VERSION 5.7 ;
  NOWIREEXTENSIONATPIN ON ;
  DIVIDERCHAR "/" ;
  BUSBITCHARS "[]" ;
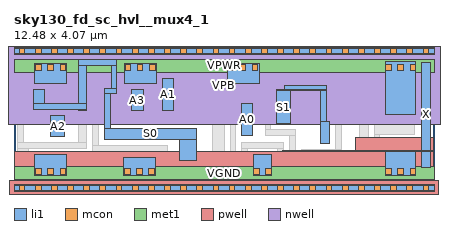
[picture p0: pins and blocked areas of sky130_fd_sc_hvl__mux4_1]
MACRO sky130_fd_sc_hvl__mux4_1
  CLASS BLOCK ;
  FOREIGN sky130_fd_sc_hvl__mux4_1 ;
  ORIGIN 0.000 0.000 ;
  SIZE 12.480 BY 4.070 ;
  PIN A0
    ANTENNAGATEAREA 0.420000 ;
    PORT
      LAYER li1 ;
        RECT 6.770 1.550 7.100 2.520 ;
    END
  END A0
  PIN A1
    ANTENNAGATEAREA 0.420000 ;
    PORT
      LAYER li1 ;
        RECT 4.400 2.300 4.730 3.260 ;
    END
  END A1
  PIN A2
    ANTENNAGATEAREA 0.420000 ;
    PORT
      LAYER li1 ;
        RECT 1.085 1.525 1.515 2.150 ;
    END
  END A2
  PIN A3
    ANTENNAGATEAREA 0.420000 ;
    PORT
      LAYER li1 ;
        RECT 3.485 2.300 3.845 2.915 ;
    END
  END A3
  PIN S0
    ANTENNAGATEAREA 1.260000 ;
    PORT
      LAYER li1 ;
        RECT 1.905 3.635 3.060 3.805 ;
        RECT 0.565 2.500 0.895 2.915 ;
        RECT 1.905 2.500 2.155 3.635 ;
        RECT 2.890 2.970 3.060 3.635 ;
        RECT 0.565 2.330 2.155 2.500 ;
        RECT 1.905 2.305 2.155 2.330 ;
        RECT 2.685 2.800 3.060 2.970 ;
        RECT 2.685 1.770 2.855 2.800 ;
        RECT 2.685 1.445 5.420 1.770 ;
        RECT 4.925 0.810 5.420 1.445 ;
    END
  END S0
  PIN S1
    ANTENNAGATEAREA 0.840000 ;
    PORT
      LAYER li1 ;
        RECT 8.050 2.915 9.290 3.055 ;
        RECT 7.810 2.885 9.290 2.915 ;
        RECT 7.810 1.920 8.220 2.885 ;
        RECT 9.120 1.985 9.290 2.885 ;
        RECT 9.120 1.315 9.370 1.985 ;
    END
  END S1
  PIN VGND
    USE GROUND ;
    PORT
      LAYER li1 ;
        RECT 0.620 0.365 1.570 0.995 ;
        RECT 3.250 0.365 4.200 0.915 ;
        RECT 7.120 0.365 7.650 0.995 ;
        RECT 11.050 0.365 11.940 1.415 ;
      LAYER mcon ;
        RECT 0.650 0.395 0.820 0.565 ;
        RECT 1.010 0.395 1.180 0.565 ;
        RECT 1.370 0.395 1.540 0.565 ;
        RECT 3.280 0.395 3.450 0.565 ;
        RECT 3.640 0.395 3.810 0.565 ;
        RECT 4.000 0.395 4.170 0.565 ;
        RECT 7.120 0.395 7.290 0.565 ;
        RECT 7.480 0.395 7.650 0.565 ;
        RECT 11.050 0.395 11.220 0.565 ;
        RECT 11.410 0.395 11.580 0.565 ;
        RECT 11.770 0.395 11.940 0.565 ;
      LAYER met1 ;
        RECT 0.000 0.255 12.480 0.625 ;
    END
  END VGND
  PIN VNB
    ANTENNADIFFAREA 2.121600 ;
    PORT
      LAYER pwell ;
        RECT 10.160 1.125 12.460 1.505 ;
        RECT 7.990 1.085 12.460 1.125 ;
        RECT 0.020 0.215 12.460 1.085 ;
        RECT -0.130 -0.215 12.610 0.215 ;
      LAYER li1 ;
        RECT 0.000 -0.085 12.480 0.085 ;
      LAYER mcon ;
        RECT 0.155 -0.085 0.325 0.085 ;
        RECT 0.635 -0.085 0.805 0.085 ;
        RECT 1.115 -0.085 1.285 0.085 ;
        RECT 1.595 -0.085 1.765 0.085 ;
        RECT 2.075 -0.085 2.245 0.085 ;
        RECT 2.555 -0.085 2.725 0.085 ;
        RECT 3.035 -0.085 3.205 0.085 ;
        RECT 3.515 -0.085 3.685 0.085 ;
        RECT 3.995 -0.085 4.165 0.085 ;
        RECT 4.475 -0.085 4.645 0.085 ;
        RECT 4.955 -0.085 5.125 0.085 ;
        RECT 5.435 -0.085 5.605 0.085 ;
        RECT 5.915 -0.085 6.085 0.085 ;
        RECT 6.395 -0.085 6.565 0.085 ;
        RECT 6.875 -0.085 7.045 0.085 ;
        RECT 7.355 -0.085 7.525 0.085 ;
        RECT 7.835 -0.085 8.005 0.085 ;
        RECT 8.315 -0.085 8.485 0.085 ;
        RECT 8.795 -0.085 8.965 0.085 ;
        RECT 9.275 -0.085 9.445 0.085 ;
        RECT 9.755 -0.085 9.925 0.085 ;
        RECT 10.235 -0.085 10.405 0.085 ;
        RECT 10.715 -0.085 10.885 0.085 ;
        RECT 11.195 -0.085 11.365 0.085 ;
        RECT 11.675 -0.085 11.845 0.085 ;
        RECT 12.155 -0.085 12.325 0.085 ;
      LAYER met1 ;
        RECT 0.000 -0.115 12.480 0.115 ;
    END
  END VNB
  PIN VPB
    ANTENNADIFFAREA 2.121600 ;
    PORT
      LAYER nwell ;
        RECT -0.330 1.885 12.810 4.485 ;
      LAYER li1 ;
        RECT 0.000 3.985 12.480 4.155 ;
      LAYER mcon ;
        RECT 0.155 3.985 0.325 4.155 ;
        RECT 0.635 3.985 0.805 4.155 ;
        RECT 1.115 3.985 1.285 4.155 ;
        RECT 1.595 3.985 1.765 4.155 ;
        RECT 2.075 3.985 2.245 4.155 ;
        RECT 2.555 3.985 2.725 4.155 ;
        RECT 3.035 3.985 3.205 4.155 ;
        RECT 3.515 3.985 3.685 4.155 ;
        RECT 3.995 3.985 4.165 4.155 ;
        RECT 4.475 3.985 4.645 4.155 ;
        RECT 4.955 3.985 5.125 4.155 ;
        RECT 5.435 3.985 5.605 4.155 ;
        RECT 5.915 3.985 6.085 4.155 ;
        RECT 6.395 3.985 6.565 4.155 ;
        RECT 6.875 3.985 7.045 4.155 ;
        RECT 7.355 3.985 7.525 4.155 ;
        RECT 7.835 3.985 8.005 4.155 ;
        RECT 8.315 3.985 8.485 4.155 ;
        RECT 8.795 3.985 8.965 4.155 ;
        RECT 9.275 3.985 9.445 4.155 ;
        RECT 9.755 3.985 9.925 4.155 ;
        RECT 10.235 3.985 10.405 4.155 ;
        RECT 10.715 3.985 10.885 4.155 ;
        RECT 11.195 3.985 11.365 4.155 ;
        RECT 11.675 3.985 11.845 4.155 ;
        RECT 12.155 3.985 12.325 4.155 ;
      LAYER met1 ;
        RECT 0.000 3.955 12.480 4.185 ;
    END
  END VPB
  PIN VPWR
    USE POWER ;
    PORT
      LAYER li1 ;
        RECT 0.620 3.095 1.570 3.705 ;
        RECT 3.270 3.095 4.220 3.705 ;
        RECT 6.330 3.095 7.280 3.705 ;
        RECT 11.050 2.175 11.940 3.755 ;
      LAYER mcon ;
        RECT 0.650 3.505 0.820 3.675 ;
        RECT 1.010 3.505 1.180 3.675 ;
        RECT 1.370 3.505 1.540 3.675 ;
        RECT 3.300 3.505 3.470 3.675 ;
        RECT 3.660 3.505 3.830 3.675 ;
        RECT 4.020 3.505 4.190 3.675 ;
        RECT 6.360 3.505 6.530 3.675 ;
        RECT 6.720 3.505 6.890 3.675 ;
        RECT 7.080 3.505 7.250 3.675 ;
        RECT 11.050 3.505 11.220 3.675 ;
        RECT 11.410 3.505 11.580 3.675 ;
        RECT 11.770 3.505 11.940 3.675 ;
      LAYER met1 ;
        RECT 0.000 3.445 12.480 3.815 ;
    END
  END VPWR
  PIN X
    ANTENNADIFFAREA 0.596250 ;
    PORT
      LAYER li1 ;
        RECT 12.120 0.605 12.370 3.735 ;
    END
  END X
  OBS
      LAYER li1 ;
        RECT 8.320 3.635 10.870 3.805 ;
        RECT 0.110 3.115 0.440 3.575 ;
        RECT 2.335 3.175 2.710 3.455 ;
        RECT 0.110 1.345 0.280 3.115 ;
        RECT 1.905 1.345 2.155 2.035 ;
        RECT 0.110 1.175 2.155 1.345 ;
        RECT 2.335 1.265 2.505 3.175 ;
        RECT 5.460 3.095 5.790 3.595 ;
        RECT 5.620 2.915 5.790 3.095 ;
        RECT 7.460 3.115 7.870 3.535 ;
        RECT 8.320 3.235 8.650 3.635 ;
        RECT 9.470 3.115 9.800 3.455 ;
        RECT 7.460 2.915 7.630 3.115 ;
        RECT 3.035 2.120 3.285 2.620 ;
        RECT 5.005 2.120 5.335 2.915 ;
        RECT 5.620 2.745 7.630 2.915 ;
        RECT 3.035 1.950 6.240 2.120 ;
        RECT 0.110 0.515 0.440 1.175 ;
        RECT 2.335 1.095 4.550 1.265 ;
        RECT 5.910 1.095 6.240 1.950 ;
        RECT 2.335 0.495 2.710 1.095 ;
        RECT 4.380 0.435 4.550 1.095 ;
        RECT 6.420 0.915 6.590 2.745 ;
        RECT 7.460 1.740 7.630 2.745 ;
        RECT 7.460 1.570 8.350 1.740 ;
        RECT 5.600 0.615 6.590 0.915 ;
        RECT 6.770 1.175 8.000 1.345 ;
        RECT 6.770 0.435 6.940 1.175 ;
        RECT 4.380 0.265 6.940 0.435 ;
        RECT 7.830 0.435 8.000 1.175 ;
        RECT 8.180 0.615 8.350 1.570 ;
        RECT 9.550 1.135 9.720 3.115 ;
        RECT 9.900 2.655 10.150 2.915 ;
        RECT 9.900 2.115 10.520 2.655 ;
        RECT 8.530 1.035 9.720 1.135 ;
        RECT 8.530 0.965 9.990 1.035 ;
        RECT 8.530 0.435 8.700 0.965 ;
        RECT 7.830 0.265 8.700 0.435 ;
        RECT 8.880 0.435 9.210 0.785 ;
        RECT 9.550 0.615 9.990 0.965 ;
        RECT 10.270 0.915 10.520 2.115 ;
        RECT 10.700 1.925 10.870 3.635 ;
        RECT 10.700 1.595 11.915 1.925 ;
        RECT 10.700 0.435 10.870 1.595 ;
        RECT 8.880 0.265 10.870 0.435 ;
  END
END sky130_fd_sc_hvl__mux4_1
END LIBRARY

